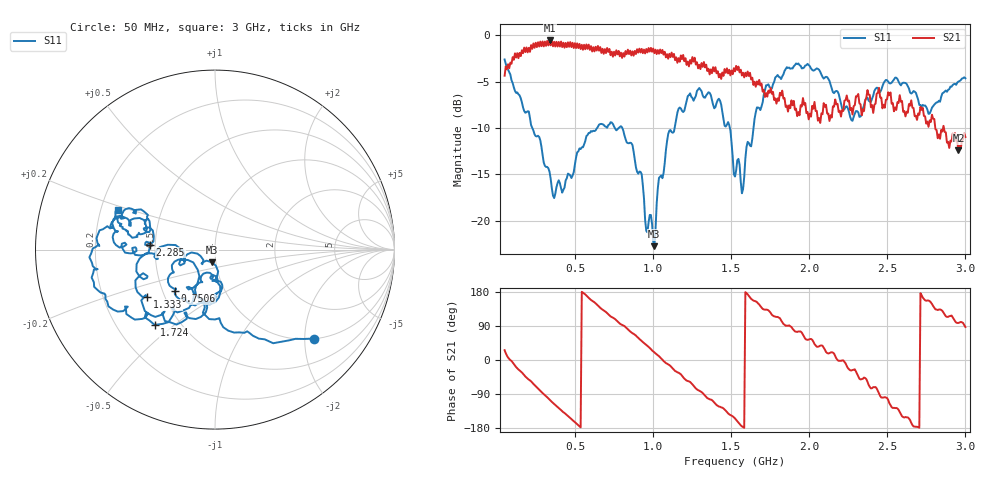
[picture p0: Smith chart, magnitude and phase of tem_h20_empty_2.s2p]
! nanovna_capture.py 2026-10-26T21:00:43+0900
! NanoVNA-F_V2 fw 0.6.0 SN 4A3639384505514B
! cal: load open short thru cal'ed  over 50000000-3000000000 Hz, 201 points
! points 401, avg 4
! TEM cell h=20 (septum+ramps trimmed ~2 mm each end), empty
# HZ S RI R 50
! S12 and S22 are not measured (written as 0)
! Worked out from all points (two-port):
!   401 points, 50 MHz to 3 GHz, reference 50 ohm
!   highest |S21| = -0.56 dB at 337.6 MHz (marker M1); lowest = -12.4 dB at 2.956 GHz (marker M2)
!   |S21| within 3 dB of the highest: 66.19 MHz to 1.289 GHz (1.223 GHz wide, 180 % of centre); 1.305 GHz to 1.345 GHz (40.03 MHz wide, 3.02 % of centre) (the widest 2 of 9)
!   lowest |S11| = -22.7 dB at 1.009 GHz (marker M3), VSWR 1.16, Z = 47.7 - j6.74 ohm
!   |S11| at or under -10 dB: 227.3 MHz to 642.1 MHz (414.8 MHz wide, 95.4 % of centre); 803.5 MHz to 1.139 GHz (335.1 MHz wide, 34.5 % of centre); 1.492 GHz to 1.644 GHz (151.5 MHz wide, 9.66 % of centre) (the widest 3 of 4)
!   S12 and S22 are empty: the file has one direction only
!   S11 on the Smith chart (normalised r, x): 50 MHz: 1.01, -2.22; 750.6 MHz: 0.58, -0.30; 1.333 GHz: 0.40, -0.27; 1.724 GHz: 0.36, -0.43; 2.285 GHz: 0.47, +0.03; 3 GHz: 0.27, +0.18
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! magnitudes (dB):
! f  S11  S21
! 50 MHz  -2.6  -4.4
! 337.6 MHz  -14.7  -0.6
! 426.1 MHz  -16.7  -0.8
! 544.1 MHz  -12.1  -1.0
! 750.6 MHz  -9.8  -1.8
! 861.2 MHz  -11.6  -2.2
! 927.6 MHz  -15.0  -1.5
! 957.1 MHz  -21.1  -1.5
! 1.009 GHz  -22.7  -1.9
! 1.038 GHz  -15.4  -2.0
! 1.164 GHz  -7.9  -2.5
! 1.333 GHz  -6.7  -3.5
! 1.429 GHz  -7.0  -4.2
! 1.525 GHz  -15.2  -3.9
! 1.577 GHz  -16.6  -4.0
! 1.724 GHz  -5.4  -6.2
! 2.019 GHz  -3.7  -7.6
! 2.285 GHz  -8.8  -7.6
! 2.513 GHz  -5.2  -6.5
! 2.771 GHz  -8.4  -9.2
! 2.956 GHz  -5.0  -12.4
! 3 GHz  -4.6  -11.0
